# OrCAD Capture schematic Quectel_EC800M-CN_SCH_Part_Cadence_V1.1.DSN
size A1

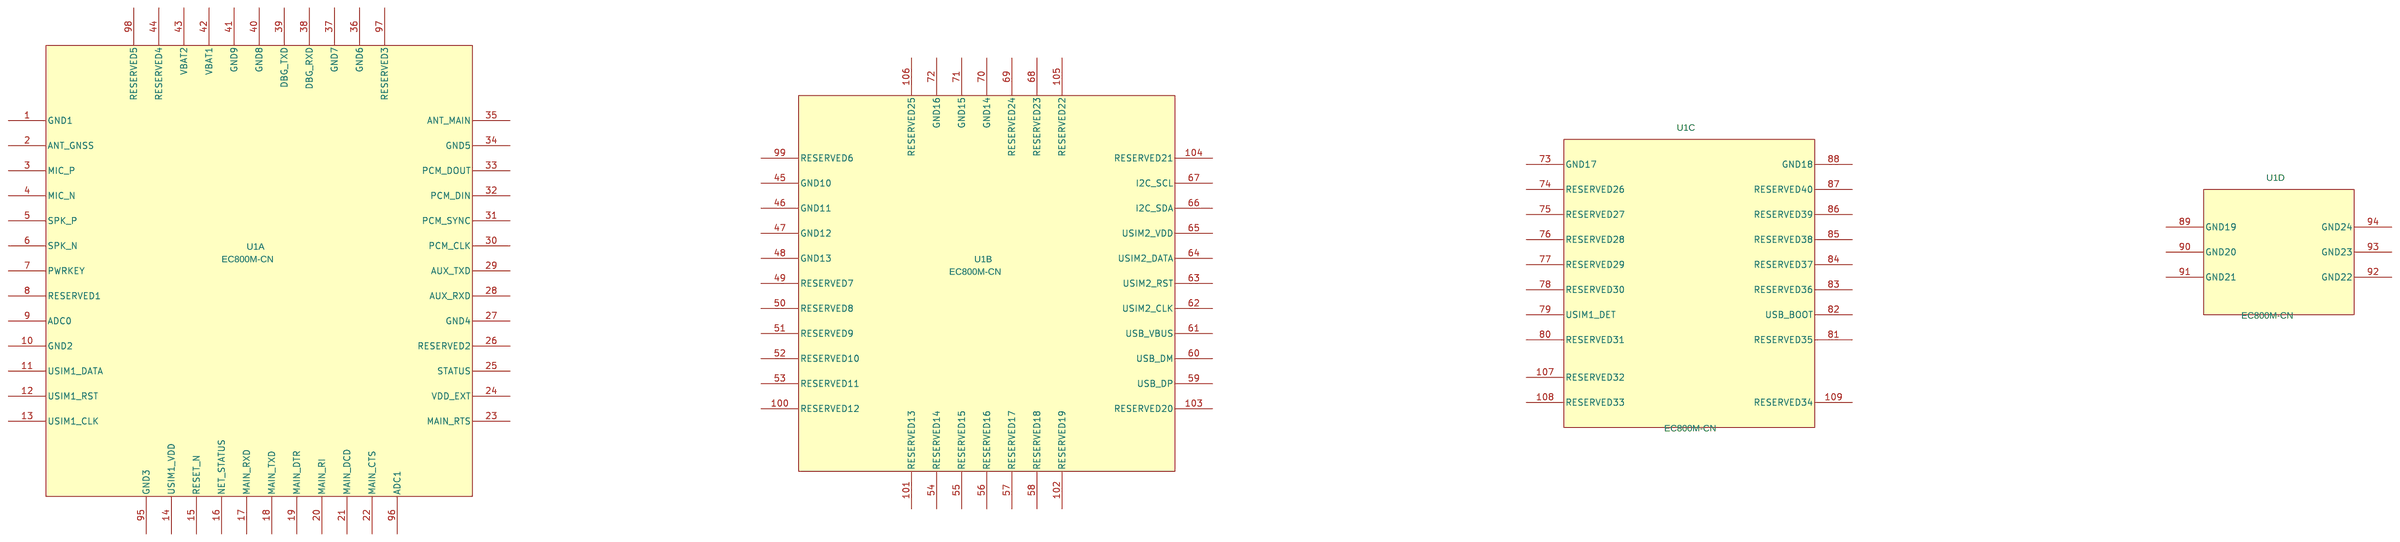
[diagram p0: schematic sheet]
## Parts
U1  EC800M-CN  [EC800M-CN]  (sections A,B,C,D)

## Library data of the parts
U1 = EC800M-CN

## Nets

Not connected (* = marked no-connect by the designer): U1 1(GND1) 2(ANT_GNSS) 3(MIC_P) 4(MIC_N) 5(SPK_P) 6(SPK_N) 7(PWRKEY) 8(RESERVED1) 9(ADC0) 10(GND2) 11(USIM1_DATA) 12(USIM1_RST) 13(USIM1_CLK) 14(USIM1_VDD) 15(RESET_N) 16(NET_STATUS) 17(MAIN_RXD) 18(MAIN_TXD) 19(MAIN_DTR) 20(MAIN_RI) 21(MAIN_DCD) 22(MAIN_CTS) 23(MAIN_RTS) 24(VDD_EXT) 25(STATUS) 26(RESERVED2) 27(GND4) 28(AUX_RXD) 29(AUX_TXD) 30(PCM_CLK) 31(PCM_SYNC) 32(PCM_DIN) 33(PCM_DOUT) 34(GND5) 35(ANT_MAIN) 36(GND6) 37(GND7) 38(DBG_RXD) 39(DBG_TXD) 40(GND8) 41(GND9) 42(VBAT1) 43(VBAT2) 44(RESERVED4) 45(GND10) 46(GND11) 47(GND12) 48(GND13) 49(RESERVED7) 50(RESERVED8) 51(RESERVED9) 52(RESERVED10) 53(RESERVED11) 54(RESERVED14) 55(RESERVED15) 56(RESERVED16) 57(RESERVED17) 58(RESERVED18) 59(USB_DP) 60(USB_DM) 61(USB_VBUS) 62(USIM2_CLK) 63(USIM2_RST) 64(USIM2_DATA) 65(USIM2_VDD) 66(I2C_SDA) 67(I2C_SCL) 68(RESERVED23) 69(RESERVED24) 70(GND14) 71(GND15) 72(GND16) 73(GND17) 74(RESERVED26) 75(RESERVED27) 76(RESERVED28) 77(RESERVED29) 78(RESERVED30) 79(USIM1_DET) 80(RESERVED31) 81(RESERVED35) 82(USB_BOOT) 83(RESERVED36) 84(RESERVED37) 85(RESERVED38) 86(RESERVED39) 87(RESERVED40) 88(GND18) 89(GND19) 90(GND20) 91(GND21) 92(GND22) 93(GND23) 94(GND24) 95(GND3) 96(ADC1) 97(RESERVED3) 98(RESERVED5) 99(RESERVED6) 100(RESERVED12) 101(RESERVED13) 102(RESERVED19) 103(RESERVED20) 104(RESERVED21) 105(RESERVED22) 106(RESERVED25) 107(RESERVED32) 108(RESERVED33) 109(RESERVED34)
